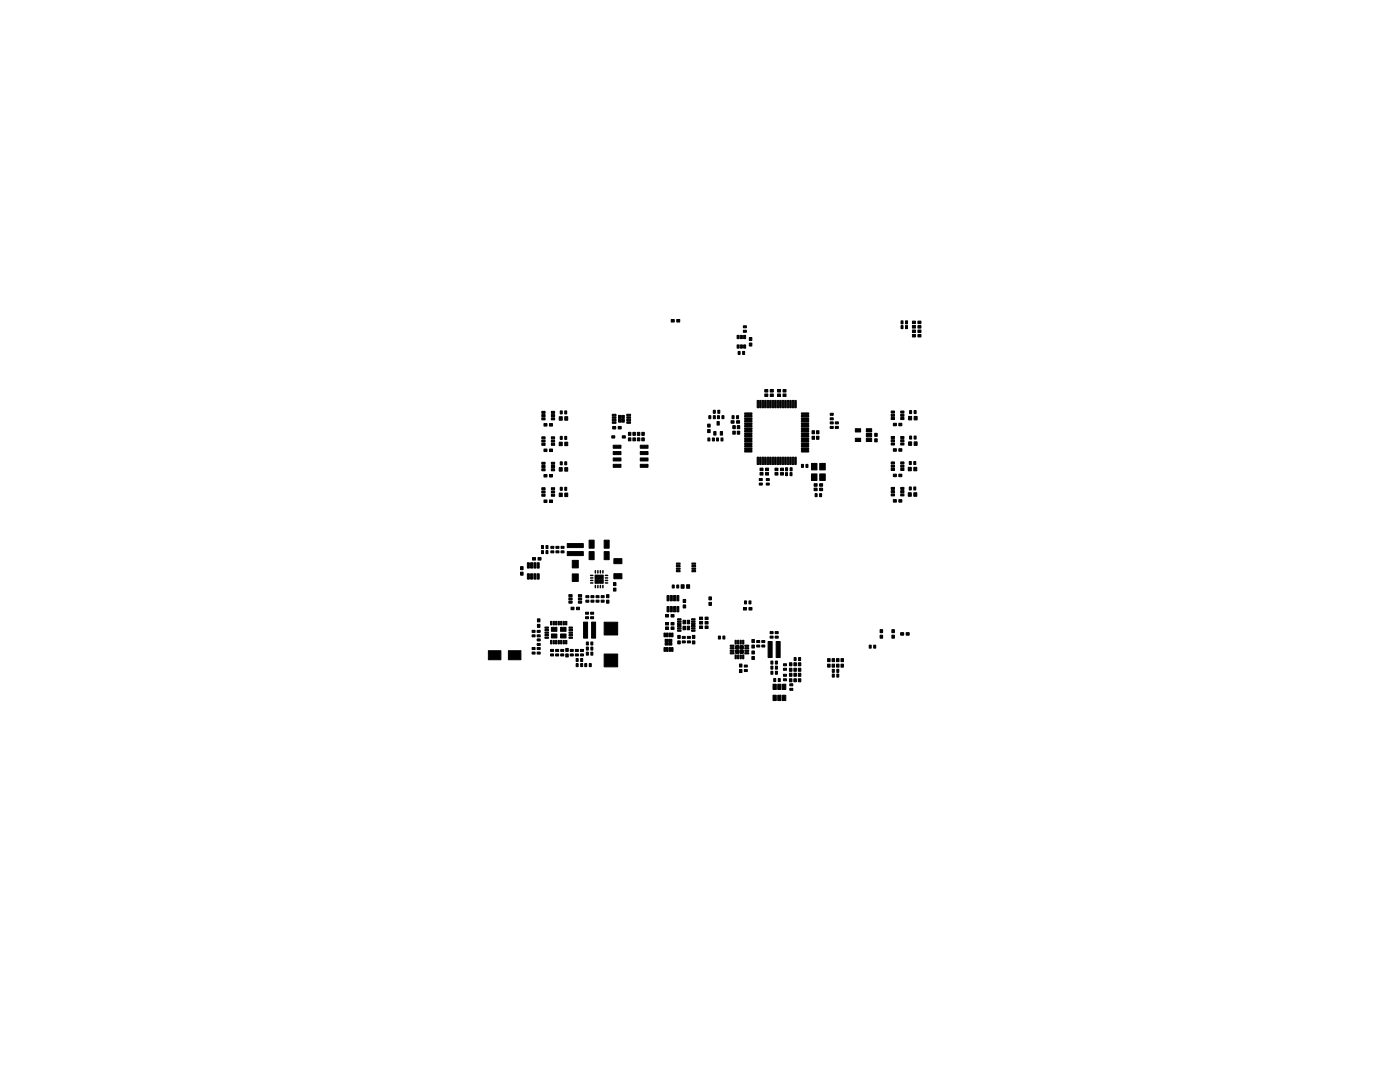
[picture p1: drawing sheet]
<svg xmlns="http://www.w3.org/2000/svg" width="279mm" height="216mm" viewBox="0 0 279 216" stroke-linecap="round" stroke-linejoin="round" font-family="sans-serif">
<g fill="#000" stroke="#000" stroke-width=".2">
<path d="M134 63.8h.6v.5h-.6zM135.1 63.8h.6v.5h-.6zM147.3 70.1h.4v.6h-.4zM147.1 66.9h.4v.7h-.4zM147.1 68.8h.4v.7h-.4zM147.8 68.8h.4v.7h-.4zM147.8 66.9h.4v.7h-.4zM148.2 70.1h.4v.6h-.4zM148.4 66.9h.4v.7h-.4zM148.4 68.8h.4v.7h-.4zM148.4 65h.6v.4h-.6zM148.4 65.9h.6v.4h-.6z"/>
<path d="M149.5 68.4h.5v.6h-.5zM149.5 67.3h.5v.6h-.5zM151.1 79.9l.3 .1-.1 1.4-.2-.1zM151.6 79.9l.3 .1-.1 1.4-.2-.1zM152.1 79.9l.3 .1-.1 1.4-.2-.1zM152.6 77.7h.6v.5h-.6zM152.6 78.6h.6v.5h-.6zM152.6 79.9l.3 .1-.1 1.4-.2-.1zM153.1 79.9l.3 .1-.1 1.4-.2-.1zM153.7 77.7h.6v.5h-.6zM153.7 78.6h.6v.5h-.6zM153.6 79.9l.3 .1-.1 1.4-.2-.1z"/>
<path d="M154.1 79.9l.3 .1-.1 1.4-.2-.1zM154.6 79.9l.3 .1-.1 1.4-.2-.1zM155.1 79.9l.3 .1-.1 1.4-.2-.1zM155.2 77.7h.6v.5h-.6zM155.2 78.6h.6v.5h-.6zM155.6 79.9l.3 .1-.1 1.4-.2-.1zM156.1 79.9l.3 .1-.1 1.4-.2-.1zM156.6 79.9l.3 .1-.1 1.4-.2-.1zM156.3 77.7h.6v.5h-.6zM156.3 78.6h.6v.5h-.6zM157.1 79.9l.3 .1-.1 1.4-.2-.1zM157.6 79.9l.3 .1-.1 1.4-.2-.1z"/>
<path d="M158.1 79.9l.3 .1-.1 1.4-.2-.1zM158.6 79.9l.3 .1-.1 1.4-.2-.1zM179.8 65h.4v.6h-.4zM179.8 64h.4v.6h-.4zM180.7 65h.4v.6h-.4zM180.7 64h.4v.6h-.4zM182.1 66.7h.6v.5h-.6zM182.1 65.9h.6v.5h-.6zM182.1 64.1h.6v.5h-.6zM182.1 65h.6v.5h-.6zM183.2 66.7h.6v.5h-.6zM183.2 65.9h.6v.5h-.6z"/>
<path d="M183.2 64.1h.6v.5h-.6zM183.2 65h.6v.5h-.6zM108.1 98h.7v.4h-.7zM108.1 98.6h.7v.4h-.7zM108.1 97.3h.7v.4h-.7zM108.1 92.9h.7v.4h-.7zM108.1 93.5h.7v.4h-.7zM108.1 92.2h.7v.4h-.7zM108.1 87.8h.7v.4h-.7zM108.1 88.5h.7v.4h-.7zM108.1 87.2h.7v.4h-.7zM108.1 82.7h.7v.4h-.7z"/>
<path d="M108.1 83.4h.7v.4h-.7zM108.1 82.1h.7v.4h-.7zM108.6 84.5h.6v.5h-.6zM108.6 99.8h.6v.5h-.6zM108.6 94.7h.6v.5h-.6zM108.6 89.6h.6v.5h-.6zM110 97.3h.7v.4h-.7zM110 98.6h.7v.4h-.7zM110 98h.7v.4h-.7zM110 92.2h.7v.4h-.7zM110 93.5h.7v.4h-.7zM110 92.9h.7v.4h-.7z"/>
<path d="M110 87.2h.7v.4h-.7zM110 88.5h.7v.4h-.7zM110 87.8h.7v.4h-.7zM110 82.1h.7v.4h-.7zM110 83.4h.7v.4h-.7zM110 82.7h.7v.4h-.7zM109.7 84.5h.6v.5h-.6zM109.7 99.8h.6v.5h-.6zM109.7 94.7h.6v.5h-.6zM109.7 89.6h.6v.5h-.6zM111.8 97.2h.4v.6h-.4zM111.8 92.2h.4v.6h-.4z"/>
<path d="M111.8 87.1h.4v.6h-.4zM111.8 82h.4v.6h-.4zM111.6 98.4h.6v.7h-.6zM111.6 93.3h.6v.7h-.6zM111.6 88.2h.6v.7h-.6zM111.6 83.1h.6v.7h-.6zM112.7 97.2h.4v.6h-.4zM112.7 92.2h.4v.6h-.4zM112.7 87.1h.4v.6h-.4zM112.7 82h.4v.6h-.4zM112.7 98.4h.6v.7h-.6zM112.7 93.3h.6v.7h-.6z"/>
<path d="M112.7 88.2h.6v.7h-.6zM112.7 83.1h.6v.7h-.6zM122.3 85.1h.6v.5h-.6zM122.4 88.8h1.5v.6h-1.5zM122.4 90.1h1.5v.6h-1.5zM122.4 91.4h1.5v.6h-1.5zM122.4 92.6h1.5v.6h-1.5zM122.1 87h.6v.4h-.6zM122.2 84.2h.7v.3h-.7zM122.2 83.7h.7v.3h-.7zM122.2 83.2h.7v.3h-.7zM122.2 82.7h.7v.3h-.7z"/>
<path d="M123.4 85.1h.6v.5h-.6zM123.4 82.9h.5v.6h-.5zM123.4 83.6h.5v.6h-.5zM124.1 82.9h.5v.6h-.5zM124.1 83.6h.5v.6h-.5zM124.2 87h.6v.4h-.6zM125.1 82.7h.7v.3h-.7zM125.1 83.2h.7v.3h-.7zM125.1 83.7h.7v.3h-.7zM125.1 84.2h.7v.3h-.7zM125.4 86.3h.5v.6h-.5zM125.4 87.4h.5v.6h-.5z"/>
<path d="M126.3 86.3h.5v.6h-.5zM126.3 87.4h.5v.6h-.5zM127.2 87.4h.5v.6h-.5zM127.2 86.3h.5v.6h-.5zM127.8 92.6h1.5v.6h-1.5zM127.8 91.4h1.5v.6h-1.5zM127.8 90.1h1.5v.6h-1.5zM127.8 88.8h1.5v.6h-1.5zM128.1 87.4h.5v.6h-.5zM128.1 86.3h.5v.6h-.5zM141.2 85.7h.5v.6h-.5zM141.2 84.6h.5v.6h-.5z"/>
<path d="M141.5 82.9h.4v.6h-.4zM141.3 87.4h.4v.6h-.4zM142.4 82.9h.4v.6h-.4zM142.4 86.1h.5v.7h-.5zM142.2 87.4h.4v.6h-.4zM142.4 81.9h.4v.6h-.4zM143 87.4h.4v.6h-.4zM143.1 84.1h.4v.7h-.4zM143.2 82.9h.4v.6h-.4zM143.3 81.9h.4v.6h-.4zM143.7 86.1h.5v.7h-.5zM143.9 87.4h.4v.6h-.4z"/>
<path d="M144.1 82.9h.4v.6h-.4zM145.9 83.9h.6v.5h-.6zM146.1 82.9h.4v.6h-.4zM146.2 84.9h.5v.6h-.5zM146.2 86h.5v.6h-.5zM147 82.9h.4v.6h-.4zM147 83.9h.6v.5h-.6zM147.1 84.9h.5v.6h-.5zM147.1 86h.5v.6h-.5zM148.6 89.9h1.4l.1 .2-1.4 .1zM148.6 89.4h1.4l.1 .2-1.4 .1zM148.6 88.9h1.4l.1 .2-1.4 .1z"/>
<path d="M148.6 88.4h1.4l.1 .2-1.4 .1zM148.6 87.9h1.4l.1 .2-1.4 .1zM148.6 87.4h1.4l.1 .2-1.4 .1zM148.6 86.9h1.4l.1 .2-1.4 .1zM148.6 86.4h1.4l.1 .2-1.4 .1zM148.6 85.9h1.4l.1 .2-1.4 .1zM148.6 85.4h1.4l.1 .2-1.4 .1zM148.6 84.9h1.4l.1 .2-1.4 .1zM148.6 84.4h1.4l.1 .2-1.4 .1zM148.6 83.9h1.4l.1 .2-1.4 .1zM148.6 83.4h1.4l.1 .2-1.4 .1zM148.6 82.9h1.4l.1 .2-1.4 .1z"/>
<path d="M148.6 82.4h1.4l.1 .2-1.4 .1zM151.1 91.2l.3 .1-.1 1.4-.2-.1zM151.5 95.5h.6v.4h-.6zM151.5 96.4h.6v.4h-.6zM151.7 94.3h.6v.5h-.6zM151.7 93.4h.6v.5h-.6zM151.6 91.2l.3 .1-.1 1.4-.2-.1zM152.1 91.2l.3 .1-.1 1.4-.2-.1zM152.8 94.3h.6v.5h-.6zM152.8 93.4h.6v.5h-.6zM152.6 91.2l.3 .1-.1 1.4-.2-.1zM152.9 96.4h.6v.4h-.6z"/>
<path d="M152.9 95.5h.6v.4h-.6zM153.1 91.2l.3 .1-.1 1.4-.2-.1zM153.6 91.2l.3 .1-.1 1.4-.2-.1zM154.1 91.2l.3 .1-.1 1.4-.2-.1zM154.6 91.2l.3 .1-.1 1.4-.2-.1zM154.7 94.3h.6v.5h-.6zM154.7 93.4h.6v.5h-.6zM155.1 91.2l.3 .1-.1 1.4-.2-.1zM155.6 91.2l.3 .1-.1 1.4-.2-.1zM156.1 91.2l.3 .1-.1 1.4-.2-.1zM155.8 94.3h.6v.5h-.6zM155.8 93.4h.6v.5h-.6z"/>
<path d="M156.8 93.3h.4v.6h-.4zM156.6 91.2l.3 .1-.1 1.4-.2-.1zM156.8 94.3h.4v.6h-.4zM157.1 91.2l.3 .1-.1 1.4-.2-.1zM157.7 93.3h.4v.6h-.4zM157.6 91.2l.3 .1-.1 1.4-.2-.1zM157.7 94.3h.4v.6h-.4zM158.1 91.2l.3 .1-.1 1.4-.2-.1zM158.6 91.2l.3 .1-.1 1.4-.2-.1zM159.9 92.7h.4v.6h-.4zM160.8 92.7h.4v.6h-.4zM160 82.4h1.3l.1 .2-1.4 .1z"/>
<path d="M160 82.9h1.3l.1 .2-1.4 .1zM160 83.4h1.3l.1 .2-1.4 .1zM160 83.9h1.3l.1 .2-1.4 .1zM160 84.4h1.3l.1 .2-1.4 .1zM160 84.9h1.3l.1 .2-1.4 .1zM160 85.4h1.3l.1 .2-1.4 .1zM160 85.9h1.3l.1 .2-1.4 .1zM160 86.4h1.3l.1 .2-1.4 .1zM160 86.9h1.3l.1 .2-1.4 .1zM160 87.4h1.3l.1 .2-1.4 .1zM160 87.9h1.3l.1 .2-1.4 .1zM160 88.4h1.3l.1 .2-1.4 .1z"/>
<path d="M160 88.9h1.3l.1 .2-1.4 .1zM160 89.4h1.3l.1 .2-1.4 .1zM160 89.9h1.3l.1 .2-1.4 .1zM162.5 97.4h.6v.5h-.6zM162.5 96.5h.6v.5h-.6zM162.1 86h.5v.6h-.5zM162.1 87.1h.5v.6h-.5zM162.7 98.5h.4v.6h-.4zM161.9 94.6h1.1v1.3h-1.1zM161.9 92.5h1.1v1.3h-1.1zM162.9 86h.5v.6h-.5zM162.9 87.1h.5v.6h-.5z"/>
<path d="M163.6 97.4h.6v.5h-.6zM163.6 96.5h.6v.5h-.6zM163.6 98.5h.4v.6h-.4zM163.6 92.5h1.1v1.3h-1.1zM163.6 94.6h1.1v1.3h-1.1zM165.7 84.2h.6v.4h-.6zM165.7 85.1h.6v.4h-.6zM165.7 82.5h.6v.4h-.6zM165.7 83.4h.6v.4h-.6zM166.7 85.1h.6v.4h-.6zM166.7 84.2h.6v.4h-.6zM170.7 87.4h1.1v.7h-1.1z"/>
<path d="M170.7 85.5h1.1v.7h-1.1zM172.9 85.5h1.1v.7h-1.1zM172.9 86.5h1.1v.6h-1.1zM172.9 87.4h1.1v.7h-1.1zM174.6 86.5h.5v.6h-.5zM174.6 87.6h.5v.6h-.5zM177.9 97.9h.6v.4h-.6zM177.9 98.6h.6v.4h-.6zM177.9 97.3h.6v.4h-.6zM177.9 92.8h.6v.4h-.6zM177.9 93.5h.6v.4h-.6zM177.9 92.2h.6v.4h-.6z"/>
<path d="M177.9 87.7h.6v.4h-.6zM177.9 88.4h.6v.4h-.6zM177.9 87.1h.6v.4h-.6zM177.9 82.7h.6v.4h-.6zM177.9 83.3h.6v.4h-.6zM177.9 82h.6v.4h-.6zM178.3 99.7h.6v.5h-.6zM178.3 94.6h.6v.5h-.6zM178.3 89.5h.6v.5h-.6zM178.3 84.5h.6v.5h-.6zM179.8 97.3h.6v.4h-.6zM179.8 98.6h.6v.4h-.6z"/>
<path d="M179.8 97.9h.6v.4h-.6zM179.8 92.2h.6v.4h-.6zM179.8 93.5h.6v.4h-.6zM179.8 92.8h.6v.4h-.6zM179.8 87.1h.6v.4h-.6zM179.8 88.4h.6v.4h-.6zM179.8 87.7h.6v.4h-.6zM179.8 82h.6v.4h-.6zM179.8 83.3h.6v.4h-.6zM179.8 82.7h.6v.4h-.6zM179.4 99.7h.6v.5h-.6zM179.4 94.6h.6v.5h-.6z"/>
<path d="M179.4 89.5h.6v.5h-.6zM179.4 84.5h.6v.5h-.6zM181.5 97.2h.4v.6h-.4zM181.5 92.1h.4v.6h-.4zM181.5 87h.4v.6h-.4zM181.5 81.9h.4v.6h-.4zM181.3 98.3h.6v.7h-.6zM181.3 93.2h.6v.7h-.6zM181.3 88.2h.6v.7h-.6zM181.3 83.1h.6v.7h-.6zM182.4 97.2h.4v.6h-.4zM182.4 92.1h.4v.6h-.4z"/>
<path d="M182.4 87h.4v.6h-.4zM182.4 81.9h.4v.6h-.4zM182.4 98.3h.6v.7h-.6zM182.4 93.2h.6v.7h-.6zM182.4 88.2h.6v.7h-.6zM182.4 83.1h.6v.7h-.6zM103.9 114.2h.5v.6h-.5zM103.9 113.1h.5v.6h-.5zM105.2 114.5h.4v1.1h-.4zM105.2 112.3h.4v1.1h-.4zM105.9 114.5h.4v1.1h-.4zM105.9 112.3h.4v1.1h-.4z"/>
<path d="M106.6 114.5h.4v1.1h-.4zM106.6 112.3h.4v1.1h-.4zM106.3 111.3h.6v.5h-.6zM107.2 114.5h.4v1.1h-.4zM107.2 112.3h.4v1.1h-.4zM107.4 111.3h.6v.5h-.6zM108.1 108.9h.4v.6h-.4zM108.1 109.9h.4v.6h-.4zM109 108.9h.4v.6h-.4zM109 109.9h.4v.6h-.4zM109.9 109h.6v.4h-.6zM109.9 109.9h.6v.4h-.6z"/>
<path d="M111 109h.6v.4h-.6zM111 109.9h.6v.4h-.6zM112 109h.6v.4h-.6zM112 109.9h.6v.4h-.6zM113.5 119.3h.7v.4h-.7zM113.5 118.7h.7v.4h-.7zM114.2 111.8h1.2v1.5h-1.2zM114.2 114.5h1.2v1.5h-1.2zM115.4 118.7h.7v.4h-.7zM115.4 119.3h.7v.4h-.7zM113.2 108.5h3.2v.8h-3.2zM113.2 110.1h3.2v.8h-3.2z"/>
<path d="M116.9 118.9h.6v.4h-.6zM117.6 107.8h1v1.6h-1zM117.6 110.1h1v1.6h-1zM117.9 118.9h.6v.4h-.6zM118.8 114.8h.7v.7h-.7zM118.8 115.7h.7v.7h-.7zM119 119.8h.6v.4h-.6zM119 118.9h.6v.4h-.6zM119.7 114.8h.7v.7h-.7zM119.7 115.7h.7v.7h-.7zM120 119.8h.6v.4h-.6zM120 118.9h.6v.4h-.6z"/>
<path d="M120.6 107.8h1v1.6h-1zM120.6 110.1h1v1.6h-1zM121 119.8h.5v.6h-.5zM121 118.7h.5v.6h-.5zM122.4 117.3h.5v.6h-.5zM122.4 116.2h.5v.6h-.5zM122.5 111.5h1.6v1h-1.6zM122.5 114.5h1.6v1h-1.6zM133.1 118.8h.4v1.1h-.4zM134.2 116.7h.4v.6h-.4zM133.8 118.8h.4v1.1h-.4zM134.4 118.8h.4v1.1h-.4z"/>
<path d="M135.1 116.7h.4v.6h-.4zM135.1 118.8h.4v1.1h-.4zM135 113.8h.7v.3h-.7zM135 113.3h.7v.3h-.7zM135 112.8h.7v.3h-.7zM135 112.3h.7v.3h-.7zM135.9 116.7h.6v.7h-.6zM137 116.7h.6v.7h-.6zM138.1 112.3h.7v.3h-.7zM138.1 112.8h.7v.3h-.7zM138.1 113.3h.7v.3h-.7zM138.1 113.8h.7v.3h-.7z"/>
<path d="M141.5 119.1h.5v.6h-.5zM97.5 129.8h2.5v1.8h-2.5zM101.5 129.8h2.5v1.8h-2.5zM106.2 130.1h.6v.4h-.6zM106.2 129.2h.6v.4h-.6zM106.2 126.7h.6v.4h-.6zM106.2 125.8h.6v.4h-.6zM107.2 130.1h.6v.4h-.6zM107.2 129.2h.6v.4h-.6zM107.2 128.4h.6v.4h-.6zM107.2 127.5h.6v.4h-.6zM107.2 126.7h.6v.4h-.6z"/>
<path d="M107.2 125.8h.6v.4h-.6zM107.3 123.5h.5v.6h-.5zM107.3 124.6h.5v.6h-.5zM108.8 127.1h.7v.3h-.7zM108.8 126.6h.7v.3h-.7zM108.8 126.1h.7v.3h-.7zM108.8 125.6h.7v.3h-.7zM108.8 125.1h.7v.3h-.7zM109.9 127.8h.2v.7h-.2zM109.9 124h.2v.7h-.2zM110 125.2h1.1v.8h-1.1zM110 126.5h1.1v.8h-1.1z"/>
<path d="M110.4 127.8h.2v.7h-.2zM110.4 124h.2v.7h-.2zM109.9 129.6h.6v.4h-.6zM109.9 130.5h.6v.4h-.6zM110.9 127.8h.2v.7h-.2zM110.9 124h.2v.7h-.2zM110.9 130.5h.6v.4h-.6zM110.9 129.6h.6v.4h-.6zM111.4 127.8h.2v.7h-.2zM111.4 124h.2v.7h-.2zM111.9 125.2h1.1v.8h-1.1zM111.9 126.5h1.1v.8h-1.1z"/>
<path d="M111.9 127.8h.2v.7h-.2zM111.9 124h.2v.7h-.2zM111.9 130.5h.6v.4h-.6zM111.9 129.6h.6v.4h-.6zM112.4 127.8h.2v.7h-.2zM112.4 124h.2v.7h-.2zM112.9 127.8h.2v.7h-.2zM112.9 124h.2v.7h-.2zM112.9 130.5h.5v.6h-.5zM112.9 129.4h.5v.6h-.5zM113.5 120h.7v.4h-.7zM113.6 125.1h.7v.3h-.7z"/>
<path d="M113.6 125.6h.7v.3h-.7zM113.6 126.1h.7v.3h-.7zM113.6 126.6h.7v.3h-.7zM113.6 127.1h.7v.3h-.7zM113.8 130.5h.6v.4h-.6zM113.8 129.6h.6v.4h-.6zM114 121.2h.6v.5h-.6zM114.8 130.5h.6v.4h-.6zM114.8 129.6h.6v.4h-.6zM115 131.4h.4v.6h-.4zM115 132.4h.4v.6h-.4zM115.4 120h.7v.4h-.7z"/>
<path d="M115.1 121.2h.6v.5h-.6zM115.9 131.4h.4v.6h-.4zM115.9 132.4h.4v.6h-.4zM115.8 129.6h.6v.4h-.6zM115.8 130.5h.6v.4h-.6zM116.5 124.1h.8v3.2h-.8zM116.9 123.1h.6v.4h-.6zM116.9 122.2h.6v.4h-.6zM117 128.1h.4v.6h-.4zM117 130.1h.4v.6h-.4zM117 129.1h.4v.6h-.4zM116.7 132.4h.4v.6h-.4z"/>
<path d="M116.9 119.8h.6v.4h-.6zM117.9 123.1h.6v.4h-.6zM117.9 122.2h.6v.4h-.6zM117.9 128.1h.4v.6h-.4zM117.9 130.1h.4v.6h-.4zM117.9 129.1h.4v.6h-.4zM117.6 132.4h.4v.6h-.4zM118.1 124.1h.8v3.2h-.8zM117.9 119.8h.6v.4h-.6zM120.6 130.5h2.7v2.6h-2.7zM120.6 124.2h2.7v2.5h-2.7zM132.5 126.3h.3v.8h-.3z"/>
<path d="M132.5 129.2h.3v.8h-.3zM132.8 122.6h.6v.5h-.6zM133 126.3h.3v.8h-.3zM133 129.2h.3v.8h-.3zM132.7 127.6h.6v.5h-.6zM132.7 128.2h.6v.5h-.6zM132.8 124.2h.6v.5h-.6zM132.8 125.1h.6v.5h-.6zM133.1 121h.4v1.1h-.4zM133.5 126.3h.3v.8h-.3zM133.5 129.2h.3v.8h-.3zM133.9 122.6h.6v.5h-.6z"/>
<path d="M133.5 127.6h.6v.5h-.6zM133.5 128.2h.6v.5h-.6zM133.8 121h.4v1.1h-.4zM134 126.3h.3v.8h-.3zM134 129.2h.3v.8h-.3zM133.9 124.2h.6v.5h-.6zM133.9 125.1h.6v.5h-.6zM134.4 121h.4v1.1h-.4zM135.1 121h.4v1.1h-.4zM135.3 127.9h.5v.6h-.5zM135.3 126.8h.5v.6h-.5zM135.2 123.5h.7v.2h-.7z"/>
<path d="M135.2 123.9h.7v.3h-.7zM135.2 124.4h.7v.2h-.7zM135.2 124.8h.7v.3h-.7zM135.2 125.3h.7v.2h-.7zM135.2 125.7h.7v.3h-.7zM136.2 127h.6v.4h-.6zM136.2 127.9h.6v.4h-.6zM136.3 123.8h.5v.7h-.5zM136.3 125h.5v.7h-.5zM136.3 119.6h.5v.6h-.5zM136.3 120.7h.5v.6h-.5zM137.1 123.8h.5v.7h-.5z"/>
<path d="M137.1 125h.5v.7h-.5zM137.2 127h.6v.4h-.6zM137.2 127.9h.6v.4h-.6zM138.2 126.8h.5v.6h-.5zM138.2 127.9h.5v.6h-.5zM138 125.7h.7v.3h-.7zM138 125.3h.7v.2h-.7zM138 124.8h.7v.3h-.7zM138 124.4h.7v.2h-.7zM138 123.9h.7v.3h-.7zM138 123.5h.7v.2h-.7zM139.6 123.1h.6v.5h-.6z"/>
<path d="M139.6 124h.6v.5h-.6zM139.6 124.9h.6v.5h-.6zM140.7 123.1h.6v.5h-.6zM140.7 124h.6v.5h-.6zM140.7 124.9h.6v.5h-.6zM141.5 120.2h.5v.6h-.5zM143.4 126.9h.4v.6h-.4zM144.3 126.9h.4v.6h-.4zM145.7 130.2h.7l.1 .2-.7 .1zM145.7 129.7h.7l.1 .2-.7 .1zM145.7 129.2h.7l.1 .2-.7 .1zM145.7 128.7h.7l.1 .2-.7 .1z"/>
<path d="M146.7 130.7h.2v.8l-.2-.1zM146.7 127.8h.2v.7h-.2zM146.8 129.7h.6v.6h-.6zM146.8 128.9h.6v.6h-.6zM147.2 130.7h.2v.8l-.2-.1zM147.2 127.8h.2v.7h-.2zM147.6 133.6h.5v.6h-.5zM147.6 132.5h.5v.6h-.5zM147.7 130.7h.2v.8l-.2-.1zM147.7 127.8h.2v.7h-.2zM147.7 129.7h.6v.6h-.6zM147.7 128.9h.6v.6h-.6z"/>
<path d="M148.2 130.7h.2v.8l-.2-.1zM148.2 127.8h.2v.7h-.2zM148.5 133.6h.6v.4h-.6zM148.5 132.7h.6v.4h-.6zM148.6 119.9h.4v.6h-.4zM148.4 121.2h.6v.5h-.6zM148.7 128.7h.7v.2l-.7 .1zM148.7 129.2h.7v.2l-.7 .1zM148.7 129.7h.7v.2l-.7 .1zM148.7 130.2h.7v.2l-.7 .1zM149.5 119.9h.4v.6h-.4zM150.1 131h.5v.6h-.5z"/>
<path d="M150.1 129.9h.5v.6h-.5zM149.5 121.2h.6v.5h-.6zM150.1 127.6h.5v.6h-.5zM150.1 128.7h.5v.6h-.5zM151 127.8h.6v.4h-.6zM151 128.7h.6v.4h-.6zM152 127.8h.6v.4h-.6zM152 128.7h.6v.4h-.6zM153.3 128h.8v3.2h-.8zM153.7 126.9h.6v.4h-.6zM153.7 126h.6v.4h-.6zM153.8 133.9h.4v.6h-.4z"/>
<path d="M153.8 132.9h.4v.6h-.4zM153.8 131.9h.4v.6h-.4zM154.3 138.7h.6v1.1h-.6zM154.3 136.5h.6v1.1h-.6zM154.4 135.4h.4v.6h-.4zM154.7 126.9h.6v.4h-.6zM154.7 126h.6v.4h-.6zM154.7 133.9h.4v.6h-.4zM154.7 132.9h.4v.6h-.4zM154.7 131.9h.4v.6h-.4zM154.9 128h.8v3.2h-.8zM155.2 138.7h.7v1.1h-.7z"/>
<path d="M155.2 136.5h.7v1.1h-.7zM155.3 135.4h.4v.6h-.4zM156.2 138.7h.6v1.1h-.6zM156.2 136.5h.6v1.1h-.6zM156.4 135.4h.6v.4h-.6zM156.4 134.5h.6v.4h-.6zM156.4 132.4h.6v.4h-.6zM156.4 133.3h.6v.4h-.6zM157.5 134.3h.5v.6h-.5zM157.5 135.4h.5v.6h-.5zM157.6 137.3h.6v.4h-.6zM157.6 136.4h.6v.4h-.6z"/>
<path d="M157.5 132.2h.5v.6h-.5zM157.5 133.3h.5v.6h-.5zM158.4 135.4h.5v.6h-.5zM158.4 134.3h.5v.6h-.5zM158.5 131.2h.4v.6h-.4zM158.4 132.2h.5v.6h-.5zM158.4 133.3h.5v.6h-.5zM159.3 135.4h.5v.6h-.5zM159.3 134.3h.5v.6h-.5zM159.4 131.2h.4v.6h-.4zM159.3 132.2h.5v.6h-.5zM159.3 133.3h.5v.6h-.5z"/>
<path d="M165.2 131.4h.5v.6h-.5zM165.2 132.5h.5v.6h-.5zM166.1 132.5h.5v.6h-.5zM166.1 131.4h.5v.6h-.5zM166.1 133.6h.4v.6h-.4zM166.1 134.5h.4v.6h-.4zM166.9 132.5h.5v.6h-.5zM166.9 131.4h.5v.6h-.5zM167 133.6h.4v.6h-.4zM167 134.5h.4v.6h-.4zM167.8 132.5h.5v.6h-.5zM167.8 131.4h.5v.6h-.5z"/>
<path d="M173.5 128.7h.4v.6h-.4zM174.4 128.7h.4v.6h-.4zM175.6 126.7h.5v.6h-.5zM175.6 125.6h.5v.6h-.5zM178 126.7h.5v.6h-.5zM178 125.6h.5v.6h-.5zM179.7 126.2h.6v.5h-.6zM180.8 126.2h.6v.5h-.6z"/>
</g>
<g fill="none" stroke="#000" stroke-width=".3">
<path d="M117.9 114.8h.4M117.9 115.3h.4M117.9 115.8h.4M117.9 116.3h.4M118.8 113.9v.4M118.8 116.8v.5M119.3 113.9v.4M119.3 116.8v.5M119.8 113.9v.4M119.8 116.8v.5M120.3 113.9v.4M120.3 116.8v.5"/>
<path d="M120.8 114.8h.5M120.8 115.3h.5M120.8 115.8h.5M120.8 116.3h.5"/>
</g>
</svg>
